VERSION 5.7 ;
BUSBITCHARS "[]" ;
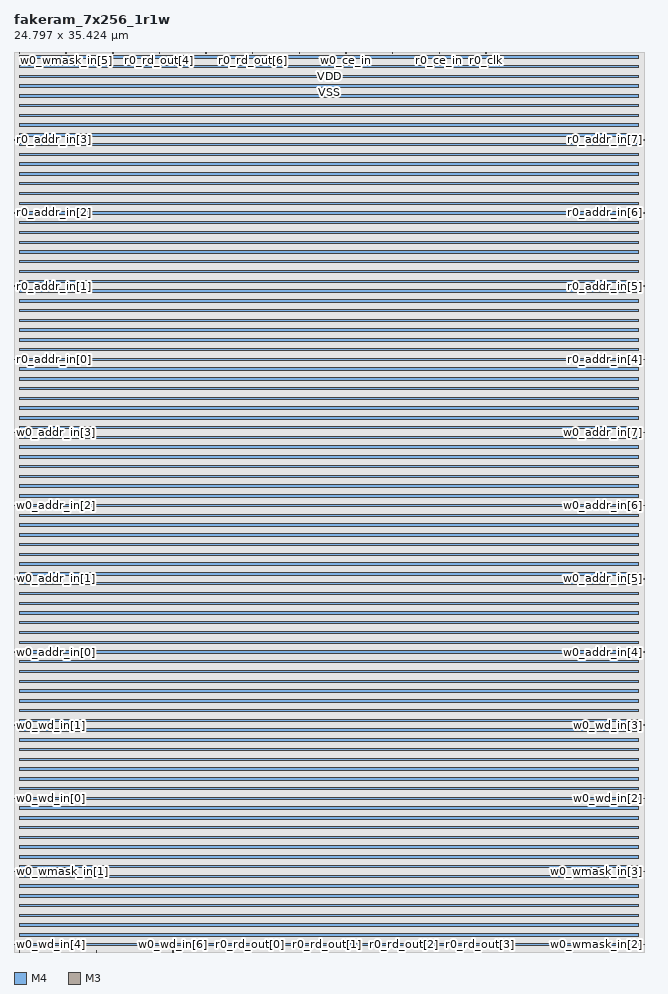
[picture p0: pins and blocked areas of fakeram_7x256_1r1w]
MACRO fakeram_7x256_1r1w
  FOREIGN fakeram_7x256_1r1w 0 0 ;
  SYMMETRY X Y R90 ;
  SIZE 24.797 BY 35.424 ;
  CLASS BLOCK ;
  PIN w0_wmask_in[0]
    DIRECTION INPUT ;
    USE SIGNAL ;
    SHAPE ABUTMENT ;
    PORT
      LAYER M4 ;
      RECT 0.000 0.276 0.072 0.300 ;
    END
  END w0_wmask_in[0]
  PIN w0_wmask_in[1]
    DIRECTION INPUT ;
    USE SIGNAL ;
    SHAPE ABUTMENT ;
    PORT
      LAYER M4 ;
      RECT 0.000 3.156 0.072 3.180 ;
    END
  END w0_wmask_in[1]
  PIN w0_wmask_in[2]
    DIRECTION INPUT ;
    USE SIGNAL ;
    SHAPE ABUTMENT ;
    PORT
      LAYER M4 ;
      RECT 24.725 0.276 24.797 0.300 ;
    END
  END w0_wmask_in[2]
  PIN w0_wmask_in[3]
    DIRECTION INPUT ;
    USE SIGNAL ;
    SHAPE ABUTMENT ;
    PORT
      LAYER M4 ;
      RECT 24.725 3.156 24.797 3.180 ;
    END
  END w0_wmask_in[3]
  PIN w0_wmask_in[4]
    DIRECTION INPUT ;
    USE SIGNAL ;
    SHAPE ABUTMENT ;
    PORT
      LAYER M3 ;
      RECT 0.207 35.370 0.225 35.424 ;
    END
  END w0_wmask_in[4]
  PIN w0_wmask_in[5]
    DIRECTION INPUT ;
    USE SIGNAL ;
    SHAPE ABUTMENT ;
    PORT
      LAYER M3 ;
      RECT 2.043 35.370 2.061 35.424 ;
    END
  END w0_wmask_in[5]
  PIN w0_wmask_in[6]
    DIRECTION INPUT ;
    USE SIGNAL ;
    SHAPE ABUTMENT ;
    PORT
      LAYER M3 ;
      RECT 3.879 35.370 3.897 35.424 ;
    END
  END w0_wmask_in[6]
  PIN w0_wd_in[0]
    DIRECTION INPUT ;
    USE SIGNAL ;
    SHAPE ABUTMENT ;
    PORT
      LAYER M4 ;
      RECT 0.000 6.036 0.072 6.060 ;
    END
  END w0_wd_in[0]
  PIN w0_wd_in[1]
    DIRECTION INPUT ;
    USE SIGNAL ;
    SHAPE ABUTMENT ;
    PORT
      LAYER M4 ;
      RECT 0.000 8.916 0.072 8.940 ;
    END
  END w0_wd_in[1]
  PIN w0_wd_in[2]
    DIRECTION INPUT ;
    USE SIGNAL ;
    SHAPE ABUTMENT ;
    PORT
      LAYER M4 ;
      RECT 24.725 6.036 24.797 6.060 ;
    END
  END w0_wd_in[2]
  PIN w0_wd_in[3]
    DIRECTION INPUT ;
    USE SIGNAL ;
    SHAPE ABUTMENT ;
    PORT
      LAYER M4 ;
      RECT 24.725 8.916 24.797 8.940 ;
    END
  END w0_wd_in[3]
  PIN w0_wd_in[4]
    DIRECTION INPUT ;
    USE SIGNAL ;
    SHAPE ABUTMENT ;
    PORT
      LAYER M3 ;
      RECT 0.207 0.000 0.225 0.054 ;
    END
  END w0_wd_in[4]
  PIN w0_wd_in[5]
    DIRECTION INPUT ;
    USE SIGNAL ;
    SHAPE ABUTMENT ;
    PORT
      LAYER M3 ;
      RECT 3.231 0.000 3.249 0.054 ;
    END
  END w0_wd_in[5]
  PIN w0_wd_in[6]
    DIRECTION INPUT ;
    USE SIGNAL ;
    SHAPE ABUTMENT ;
    PORT
      LAYER M3 ;
      RECT 6.255 0.000 6.273 0.054 ;
    END
  END w0_wd_in[6]
  PIN r0_rd_out[0]
    DIRECTION OUTPUT ;
    USE SIGNAL ;
    SHAPE ABUTMENT ;
    PORT
      LAYER M3 ;
      RECT 9.279 0.000 9.297 0.054 ;
    END
  END r0_rd_out[0]
  PIN r0_rd_out[1]
    DIRECTION OUTPUT ;
    USE SIGNAL ;
    SHAPE ABUTMENT ;
    PORT
      LAYER M3 ;
      RECT 12.303 0.000 12.321 0.054 ;
    END
  END r0_rd_out[1]
  PIN r0_rd_out[2]
    DIRECTION OUTPUT ;
    USE SIGNAL ;
    SHAPE ABUTMENT ;
    PORT
      LAYER M3 ;
      RECT 15.327 0.000 15.345 0.054 ;
    END
  END r0_rd_out[2]
  PIN r0_rd_out[3]
    DIRECTION OUTPUT ;
    USE SIGNAL ;
    SHAPE ABUTMENT ;
    PORT
      LAYER M3 ;
      RECT 18.351 0.000 18.369 0.054 ;
    END
  END r0_rd_out[3]
  PIN r0_rd_out[4]
    DIRECTION OUTPUT ;
    USE SIGNAL ;
    SHAPE ABUTMENT ;
    PORT
      LAYER M3 ;
      RECT 5.715 35.370 5.733 35.424 ;
    END
  END r0_rd_out[4]
  PIN r0_rd_out[5]
    DIRECTION OUTPUT ;
    USE SIGNAL ;
    SHAPE ABUTMENT ;
    PORT
      LAYER M3 ;
      RECT 7.551 35.370 7.569 35.424 ;
    END
  END r0_rd_out[5]
  PIN r0_rd_out[6]
    DIRECTION OUTPUT ;
    USE SIGNAL ;
    SHAPE ABUTMENT ;
    PORT
      LAYER M3 ;
      RECT 9.387 35.370 9.405 35.424 ;
    END
  END r0_rd_out[6]
  PIN w0_addr_in[0]
    DIRECTION INPUT ;
    USE SIGNAL ;
    SHAPE ABUTMENT ;
    PORT
      LAYER M4 ;
      RECT 0.000 11.796 0.072 11.820 ;
    END
  END w0_addr_in[0]
  PIN w0_addr_in[1]
    DIRECTION INPUT ;
    USE SIGNAL ;
    SHAPE ABUTMENT ;
    PORT
      LAYER M4 ;
      RECT 0.000 14.676 0.072 14.700 ;
    END
  END w0_addr_in[1]
  PIN w0_addr_in[2]
    DIRECTION INPUT ;
    USE SIGNAL ;
    SHAPE ABUTMENT ;
    PORT
      LAYER M4 ;
      RECT 0.000 17.556 0.072 17.580 ;
    END
  END w0_addr_in[2]
  PIN w0_addr_in[3]
    DIRECTION INPUT ;
    USE SIGNAL ;
    SHAPE ABUTMENT ;
    PORT
      LAYER M4 ;
      RECT 0.000 20.436 0.072 20.460 ;
    END
  END w0_addr_in[3]
  PIN w0_addr_in[4]
    DIRECTION INPUT ;
    USE SIGNAL ;
    SHAPE ABUTMENT ;
    PORT
      LAYER M4 ;
      RECT 24.725 11.796 24.797 11.820 ;
    END
  END w0_addr_in[4]
  PIN w0_addr_in[5]
    DIRECTION INPUT ;
    USE SIGNAL ;
    SHAPE ABUTMENT ;
    PORT
      LAYER M4 ;
      RECT 24.725 14.676 24.797 14.700 ;
    END
  END w0_addr_in[5]
  PIN w0_addr_in[6]
    DIRECTION INPUT ;
    USE SIGNAL ;
    SHAPE ABUTMENT ;
    PORT
      LAYER M4 ;
      RECT 24.725 17.556 24.797 17.580 ;
    END
  END w0_addr_in[6]
  PIN w0_addr_in[7]
    DIRECTION INPUT ;
    USE SIGNAL ;
    SHAPE ABUTMENT ;
    PORT
      LAYER M4 ;
      RECT 24.725 20.436 24.797 20.460 ;
    END
  END w0_addr_in[7]
  PIN r0_addr_in[0]
    DIRECTION INPUT ;
    USE SIGNAL ;
    SHAPE ABUTMENT ;
    PORT
      LAYER M4 ;
      RECT 0.000 23.316 0.072 23.340 ;
    END
  END r0_addr_in[0]
  PIN r0_addr_in[1]
    DIRECTION INPUT ;
    USE SIGNAL ;
    SHAPE ABUTMENT ;
    PORT
      LAYER M4 ;
      RECT 0.000 26.196 0.072 26.220 ;
    END
  END r0_addr_in[1]
  PIN r0_addr_in[2]
    DIRECTION INPUT ;
    USE SIGNAL ;
    SHAPE ABUTMENT ;
    PORT
      LAYER M4 ;
      RECT 0.000 29.076 0.072 29.100 ;
    END
  END r0_addr_in[2]
  PIN r0_addr_in[3]
    DIRECTION INPUT ;
    USE SIGNAL ;
    SHAPE ABUTMENT ;
    PORT
      LAYER M4 ;
      RECT 0.000 31.956 0.072 31.980 ;
    END
  END r0_addr_in[3]
  PIN r0_addr_in[4]
    DIRECTION INPUT ;
    USE SIGNAL ;
    SHAPE ABUTMENT ;
    PORT
      LAYER M4 ;
      RECT 24.725 23.316 24.797 23.340 ;
    END
  END r0_addr_in[4]
  PIN r0_addr_in[5]
    DIRECTION INPUT ;
    USE SIGNAL ;
    SHAPE ABUTMENT ;
    PORT
      LAYER M4 ;
      RECT 24.725 26.196 24.797 26.220 ;
    END
  END r0_addr_in[5]
  PIN r0_addr_in[6]
    DIRECTION INPUT ;
    USE SIGNAL ;
    SHAPE ABUTMENT ;
    PORT
      LAYER M4 ;
      RECT 24.725 29.076 24.797 29.100 ;
    END
  END r0_addr_in[6]
  PIN r0_addr_in[7]
    DIRECTION INPUT ;
    USE SIGNAL ;
    SHAPE ABUTMENT ;
    PORT
      LAYER M4 ;
      RECT 24.725 31.956 24.797 31.980 ;
    END
  END r0_addr_in[7]
  PIN w0_we_in
    DIRECTION INPUT ;
    USE SIGNAL ;
    SHAPE ABUTMENT ;
    PORT
      LAYER M3 ;
      RECT 11.223 35.370 11.241 35.424 ;
    END
  END w0_we_in
  PIN w0_ce_in
    DIRECTION INPUT ;
    USE SIGNAL ;
    SHAPE ABUTMENT ;
    PORT
      LAYER M3 ;
      RECT 13.059 35.370 13.077 35.424 ;
    END
  END w0_ce_in
  PIN w0_clk
    DIRECTION INPUT ;
    USE SIGNAL ;
    SHAPE ABUTMENT ;
    PORT
      LAYER M3 ;
      RECT 14.895 35.370 14.913 35.424 ;
    END
  END w0_clk
  PIN r0_ce_in
    DIRECTION INPUT ;
    USE SIGNAL ;
    SHAPE ABUTMENT ;
    PORT
      LAYER M3 ;
      RECT 16.731 35.370 16.749 35.424 ;
    END
  END r0_ce_in
  PIN r0_clk
    DIRECTION INPUT ;
    USE SIGNAL ;
    SHAPE ABUTMENT ;
    PORT
      LAYER M3 ;
      RECT 18.567 35.370 18.585 35.424 ;
    END
  END r0_clk
  PIN VSS
    DIRECTION INOUT ;
    USE GROUND ;
    PORT
      LAYER M4 ;
      RECT 0.216 0.240 24.581 0.336 ;
      RECT 0.216 1.008 24.581 1.104 ;
      RECT 0.216 1.776 24.581 1.872 ;
      RECT 0.216 2.544 24.581 2.640 ;
      RECT 0.216 3.312 24.581 3.408 ;
      RECT 0.216 4.080 24.581 4.176 ;
      RECT 0.216 4.848 24.581 4.944 ;
      RECT 0.216 5.616 24.581 5.712 ;
      RECT 0.216 6.384 24.581 6.480 ;
      RECT 0.216 7.152 24.581 7.248 ;
      RECT 0.216 7.920 24.581 8.016 ;
      RECT 0.216 8.688 24.581 8.784 ;
      RECT 0.216 9.456 24.581 9.552 ;
      RECT 0.216 10.224 24.581 10.320 ;
      RECT 0.216 10.992 24.581 11.088 ;
      RECT 0.216 11.760 24.581 11.856 ;
      RECT 0.216 12.528 24.581 12.624 ;
      RECT 0.216 13.296 24.581 13.392 ;
      RECT 0.216 14.064 24.581 14.160 ;
      RECT 0.216 14.832 24.581 14.928 ;
      RECT 0.216 15.600 24.581 15.696 ;
      RECT 0.216 16.368 24.581 16.464 ;
      RECT 0.216 17.136 24.581 17.232 ;
      RECT 0.216 17.904 24.581 18.000 ;
      RECT 0.216 18.672 24.581 18.768 ;
      RECT 0.216 19.440 24.581 19.536 ;
      RECT 0.216 20.208 24.581 20.304 ;
      RECT 0.216 20.976 24.581 21.072 ;
      RECT 0.216 21.744 24.581 21.840 ;
      RECT 0.216 22.512 24.581 22.608 ;
      RECT 0.216 23.280 24.581 23.376 ;
      RECT 0.216 24.048 24.581 24.144 ;
      RECT 0.216 24.816 24.581 24.912 ;
      RECT 0.216 25.584 24.581 25.680 ;
      RECT 0.216 26.352 24.581 26.448 ;
      RECT 0.216 27.120 24.581 27.216 ;
      RECT 0.216 27.888 24.581 27.984 ;
      RECT 0.216 28.656 24.581 28.752 ;
      RECT 0.216 29.424 24.581 29.520 ;
      RECT 0.216 30.192 24.581 30.288 ;
      RECT 0.216 30.960 24.581 31.056 ;
      RECT 0.216 31.728 24.581 31.824 ;
      RECT 0.216 32.496 24.581 32.592 ;
      RECT 0.216 33.264 24.581 33.360 ;
      RECT 0.216 34.032 24.581 34.128 ;
      RECT 0.216 34.800 24.581 34.896 ;
    END
  END VSS
  PIN VDD
    DIRECTION INOUT ;
    USE POWER ;
    PORT
      LAYER M4 ;
      RECT 0.216 0.624 24.581 0.720 ;
      RECT 0.216 1.392 24.581 1.488 ;
      RECT 0.216 2.160 24.581 2.256 ;
      RECT 0.216 2.928 24.581 3.024 ;
      RECT 0.216 3.696 24.581 3.792 ;
      RECT 0.216 4.464 24.581 4.560 ;
      RECT 0.216 5.232 24.581 5.328 ;
      RECT 0.216 6.000 24.581 6.096 ;
      RECT 0.216 6.768 24.581 6.864 ;
      RECT 0.216 7.536 24.581 7.632 ;
      RECT 0.216 8.304 24.581 8.400 ;
      RECT 0.216 9.072 24.581 9.168 ;
      RECT 0.216 9.840 24.581 9.936 ;
      RECT 0.216 10.608 24.581 10.704 ;
      RECT 0.216 11.376 24.581 11.472 ;
      RECT 0.216 12.144 24.581 12.240 ;
      RECT 0.216 12.912 24.581 13.008 ;
      RECT 0.216 13.680 24.581 13.776 ;
      RECT 0.216 14.448 24.581 14.544 ;
      RECT 0.216 15.216 24.581 15.312 ;
      RECT 0.216 15.984 24.581 16.080 ;
      RECT 0.216 16.752 24.581 16.848 ;
      RECT 0.216 17.520 24.581 17.616 ;
      RECT 0.216 18.288 24.581 18.384 ;
      RECT 0.216 19.056 24.581 19.152 ;
      RECT 0.216 19.824 24.581 19.920 ;
      RECT 0.216 20.592 24.581 20.688 ;
      RECT 0.216 21.360 24.581 21.456 ;
      RECT 0.216 22.128 24.581 22.224 ;
      RECT 0.216 22.896 24.581 22.992 ;
      RECT 0.216 23.664 24.581 23.760 ;
      RECT 0.216 24.432 24.581 24.528 ;
      RECT 0.216 25.200 24.581 25.296 ;
      RECT 0.216 25.968 24.581 26.064 ;
      RECT 0.216 26.736 24.581 26.832 ;
      RECT 0.216 27.504 24.581 27.600 ;
      RECT 0.216 28.272 24.581 28.368 ;
      RECT 0.216 29.040 24.581 29.136 ;
      RECT 0.216 29.808 24.581 29.904 ;
      RECT 0.216 30.576 24.581 30.672 ;
      RECT 0.216 31.344 24.581 31.440 ;
      RECT 0.216 32.112 24.581 32.208 ;
      RECT 0.216 32.880 24.581 32.976 ;
      RECT 0.216 33.648 24.581 33.744 ;
      RECT 0.216 34.416 24.581 34.512 ;
      RECT 0.216 35.184 24.581 35.280 ;
    END
  END VDD
  OBS
    LAYER M1 ;
    RECT 0 0 24.797 35.424 ;
    LAYER M2 ;
    RECT 0 0 24.797 35.424 ;
    LAYER M3 ;
    RECT 0 0 24.797 35.424 ;
    LAYER M4 ;
    RECT 0 0 24.797 35.424 ;
  END
END fakeram_7x256_1r1w

END LIBRARY
